VERSION 5.7 ;
  NOWIREEXTENSIONATPIN ON ;
  DIVIDERCHAR "/" ;
  BUSBITCHARS "[]" ;
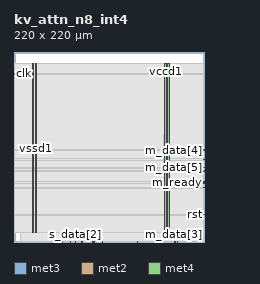
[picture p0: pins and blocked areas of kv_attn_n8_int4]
MACRO kv_attn_n8_int4
  CLASS BLOCK ;
  FOREIGN kv_attn_n8_int4 ;
  ORIGIN 0.000 0.000 ;
  SIZE 220.000 BY 220.000 ;
  PIN clk
    DIRECTION INPUT ;
    USE SIGNAL ;
    ANTENNAGATEAREA 1.286700 ;
    ANTENNADIFFAREA 0.434700 ;
    PORT
      LAYER met3 ;
        RECT 0.000 194.520 0.600 195.120 ;
    END
  END clk
  PIN m_data[0]
    DIRECTION OUTPUT ;
    USE SIGNAL ;
    ANTENNADIFFAREA 0.702900 ;
    PORT
      LAYER met2 ;
        RECT 186.850 0.000 187.130 0.280 ;
    END
  END m_data[0]
  PIN m_data[1]
    DIRECTION OUTPUT ;
    USE SIGNAL ;
    ANTENNADIFFAREA 0.702900 ;
    PORT
      LAYER met2 ;
        RECT 185.930 0.000 186.210 0.280 ;
    END
  END m_data[1]
  PIN m_data[2]
    DIRECTION OUTPUT ;
    USE SIGNAL ;
    ANTENNADIFFAREA 0.702900 ;
    PORT
      LAYER met2 ;
        RECT 142.690 0.000 142.970 0.280 ;
    END
  END m_data[2]
  PIN m_data[3]
    DIRECTION OUTPUT ;
    USE SIGNAL ;
    ANTENNADIFFAREA 0.702900 ;
    PORT
      LAYER met2 ;
        RECT 189.610 0.000 189.890 0.280 ;
    END
  END m_data[3]
  PIN m_data[4]
    DIRECTION OUTPUT ;
    USE SIGNAL ;
    ANTENNADIFFAREA 0.702900 ;
    PORT
      LAYER met3 ;
        RECT 219.400 106.120 220.000 106.720 ;
    END
  END m_data[4]
  PIN m_data[5]
    DIRECTION OUTPUT ;
    USE SIGNAL ;
    ANTENNADIFFAREA 0.702900 ;
    PORT
      LAYER met3 ;
        RECT 219.400 85.720 220.000 86.320 ;
    END
  END m_data[5]
  PIN m_data[6]
    DIRECTION OUTPUT ;
    USE SIGNAL ;
    ANTENNADIFFAREA 0.702900 ;
    PORT
      LAYER met3 ;
        RECT 219.400 95.240 220.000 95.840 ;
    END
  END m_data[6]
  PIN m_data[7]
    DIRECTION OUTPUT ;
    USE SIGNAL ;
    ANTENNADIFFAREA 0.702900 ;
    PORT
      LAYER met3 ;
        RECT 219.400 81.640 220.000 82.240 ;
    END
  END m_data[7]
  PIN m_last
    DIRECTION OUTPUT ;
    USE SIGNAL ;
    ANTENNADIFFAREA 0.702900 ;
    PORT
      LAYER met3 ;
        RECT 219.400 62.600 220.000 63.200 ;
    END
  END m_last
  PIN m_ready
    DIRECTION INPUT ;
    USE SIGNAL ;
    ANTENNAGATEAREA 0.647700 ;
    ANTENNADIFFAREA 0.434700 ;
    PORT
      LAYER met3 ;
        RECT 219.400 68.040 220.000 68.640 ;
    END
  END m_ready
  PIN m_valid
    DIRECTION OUTPUT ;
    USE SIGNAL ;
    ANTENNADIFFAREA 0.702900 ;
    PORT
      LAYER met3 ;
        RECT 219.400 69.400 220.000 70.000 ;
    END
  END m_valid
  PIN rst
    DIRECTION INPUT ;
    USE SIGNAL ;
    ANTENNAGATEAREA 0.647700 ;
    ANTENNADIFFAREA 0.434700 ;
    PORT
      LAYER met3 ;
        RECT 219.400 31.320 220.000 31.920 ;
    END
  END rst
  PIN s_data[0]
    DIRECTION INPUT ;
    USE SIGNAL ;
    ANTENNAGATEAREA 0.647700 ;
    ANTENNADIFFAREA 0.434700 ;
    PORT
      LAYER met2 ;
        RECT 79.210 0.000 79.490 0.280 ;
    END
  END s_data[0]
  PIN s_data[1]
    DIRECTION INPUT ;
    USE SIGNAL ;
    ANTENNAGATEAREA 0.647700 ;
    ANTENNADIFFAREA 0.434700 ;
    PORT
      LAYER met2 ;
        RECT 102.210 0.000 102.490 0.280 ;
    END
  END s_data[1]
  PIN s_data[2]
    DIRECTION INPUT ;
    USE SIGNAL ;
    ANTENNAGATEAREA 0.647700 ;
    ANTENNADIFFAREA 0.434700 ;
    PORT
      LAYER met2 ;
        RECT 70.930 0.000 71.210 0.280 ;
    END
  END s_data[2]
  PIN s_data[3]
    DIRECTION INPUT ;
    USE SIGNAL ;
    ANTENNAGATEAREA 0.647700 ;
    ANTENNADIFFAREA 0.434700 ;
    PORT
      LAYER met2 ;
        RECT 54.370 0.000 54.650 0.280 ;
    END
  END s_data[3]
  PIN s_data[4]
    DIRECTION INPUT ;
    USE SIGNAL ;
    ANTENNAGATEAREA 0.647700 ;
    ANTENNADIFFAREA 0.434700 ;
    PORT
      LAYER met2 ;
        RECT 55.290 0.000 55.570 0.280 ;
    END
  END s_data[4]
  PIN s_data[5]
    DIRECTION INPUT ;
    USE SIGNAL ;
    ANTENNAGATEAREA 0.647700 ;
    ANTENNADIFFAREA 0.434700 ;
    PORT
      LAYER met2 ;
        RECT 56.210 0.000 56.490 0.280 ;
    END
  END s_data[5]
  PIN s_data[6]
    DIRECTION INPUT ;
    USE SIGNAL ;
    ANTENNAGATEAREA 0.647700 ;
    ANTENNADIFFAREA 0.434700 ;
    PORT
      LAYER met2 ;
        RECT 78.290 0.000 78.570 0.280 ;
    END
  END s_data[6]
  PIN s_data[7]
    DIRECTION INPUT ;
    USE SIGNAL ;
    ANTENNAGATEAREA 0.647700 ;
    ANTENNADIFFAREA 0.434700 ;
    PORT
      LAYER met2 ;
        RECT 65.410 0.000 65.690 0.280 ;
    END
  END s_data[7]
  PIN s_last
    DIRECTION INPUT ;
    USE SIGNAL ;
    ANTENNAGATEAREA 0.647700 ;
    ANTENNADIFFAREA 0.434700 ;
    PORT
      LAYER met2 ;
        RECT 91.170 0.000 91.450 0.280 ;
    END
  END s_last
  PIN s_ready
    DIRECTION OUTPUT ;
    USE SIGNAL ;
    ANTENNADIFFAREA 0.702900 ;
    PORT
      LAYER met2 ;
        RECT 93.010 0.000 93.290 0.280 ;
    END
  END s_ready
  PIN s_valid
    DIRECTION INPUT ;
    USE SIGNAL ;
    ANTENNAGATEAREA 0.647700 ;
    ANTENNADIFFAREA 0.434700 ;
    PORT
      LAYER met2 ;
        RECT 92.090 0.000 92.370 0.280 ;
    END
  END s_valid
  PIN vccd1
    DIRECTION INOUT ;
    USE POWER ;
    PORT
      LAYER met4 ;
        RECT 21.040 10.640 22.640 206.960 ;
    END
    PORT
      LAYER met4 ;
        RECT 174.640 10.640 176.240 206.960 ;
    END
  END vccd1
  PIN vssd1
    DIRECTION INOUT ;
    USE GROUND ;
    PORT
      LAYER met4 ;
        RECT 24.340 10.640 25.940 206.960 ;
    END
    PORT
      LAYER met4 ;
        RECT 177.940 10.640 179.540 206.960 ;
    END
  END vssd1
  OBS
      LAYER nwell ;
        RECT 5.330 10.795 214.550 206.805 ;
      LAYER li1 ;
        RECT 5.520 10.795 214.360 206.805 ;
      LAYER met1 ;
        RECT 5.520 10.640 214.360 206.960 ;
      LAYER met2 ;
        RECT 7.000 0.560 212.890 206.905 ;
        RECT 7.000 0.070 54.090 0.560 ;
        RECT 54.930 0.070 55.010 0.560 ;
        RECT 55.850 0.070 55.930 0.560 ;
        RECT 56.770 0.070 65.130 0.560 ;
        RECT 65.970 0.070 70.650 0.560 ;
        RECT 71.490 0.070 78.010 0.560 ;
        RECT 78.850 0.070 78.930 0.560 ;
        RECT 79.770 0.070 90.890 0.560 ;
        RECT 91.730 0.070 91.810 0.560 ;
        RECT 92.650 0.070 92.730 0.560 ;
        RECT 93.570 0.070 101.930 0.560 ;
        RECT 102.770 0.070 142.410 0.560 ;
        RECT 143.250 0.070 185.650 0.560 ;
        RECT 186.490 0.070 186.570 0.560 ;
        RECT 187.410 0.070 189.330 0.560 ;
        RECT 190.170 0.070 212.890 0.560 ;
      LAYER met3 ;
        RECT 0.600 195.520 219.400 206.885 ;
        RECT 1.000 194.120 219.400 195.520 ;
        RECT 0.600 107.120 219.400 194.120 ;
        RECT 0.600 105.720 219.000 107.120 ;
        RECT 0.600 96.240 219.400 105.720 ;
        RECT 0.600 94.840 219.000 96.240 ;
        RECT 0.600 86.720 219.400 94.840 ;
        RECT 0.600 85.320 219.000 86.720 ;
        RECT 0.600 82.640 219.400 85.320 ;
        RECT 0.600 81.240 219.000 82.640 ;
        RECT 0.600 70.400 219.400 81.240 ;
        RECT 0.600 67.640 219.000 70.400 ;
        RECT 0.600 63.600 219.400 67.640 ;
        RECT 0.600 62.200 219.000 63.600 ;
        RECT 0.600 32.320 219.400 62.200 ;
        RECT 0.600 30.920 219.000 32.320 ;
        RECT 0.600 10.715 219.400 30.920 ;
      LAYER met4 ;
        RECT 173.255 81.095 173.585 124.945 ;
  END
END kv_attn_n8_int4
END LIBRARY

